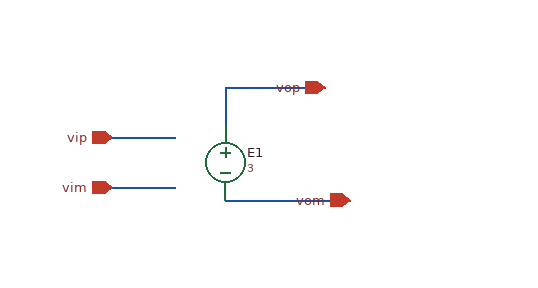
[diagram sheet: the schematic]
v {xschem version=3.4.8RC file_version=1.2}
G {}
K {}
V {}
S {}
E {}
N -90 -40 -40 -40 {lab=vip}
N -90 -0 -40 -0 {lab=vim}
N -0 -80 0 -50 {lab=vop}
N -0 -80 80 -80 {lab=vop}
N -0 10 100 10 {lab=vom}
C {vcvs.sym} 0 -20 0 0 {name=E1 value=3}
C {iopin.sym} -90 -40 2 0 {name=p1 lab=vip}
C {iopin.sym} -90 0 2 0 {name=p2 lab=vim}
C {iopin.sym} 80 -80 0 0 {name=p3 lab=vop}
C {iopin.sym} 100 10 0 0 {name=p4 lab=vom}
